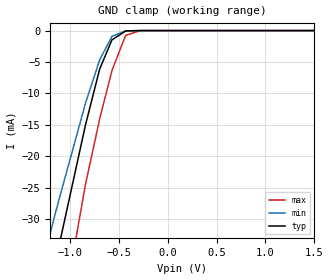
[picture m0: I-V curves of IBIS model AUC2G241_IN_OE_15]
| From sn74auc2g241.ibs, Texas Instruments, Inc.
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[Model]   AUC2G241_IN_OE_15
Model_type  Input
Vinl=0.49
Vinh=1.04
| variable   typ   min   max
C_comp   2.67pF   2.22pF   3.05pF
[Temperature Range]   40   100   -40
| Ambient temperature   25   85   -40
[Voltage range]   1.5   1.4   1.6
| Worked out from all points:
|   GND clamp passes 1 mA (typ) near -0.55 V on its own axis
[GND Clamp]
| AUC2G241_IN_OE_15
|   Voltage   I(typ)   I(min)   I(max)
-3.6V     -223.1mA   -186.8mA   -268.3mA
-1.505V   -63.61mA   -50.93mA   -83.59mA
-1.46V    -60.22mA   -48.13mA   -79.57mA
-1.325V   -50.08mA   -39.79mA   -67.5mA
-1.17V    -38.57mA   -30.39mA   -53.61mA
-1.12V    -34.89mA   -27.41mA   -49.13mA
-840mV    -15.01mA   -11.55mA   -24.46mA
-695mV    -6.121mA   -4.657mA   -14.06mA
-570mV    -1.488mA   -922uA     -6.381mA
-430mV    -73.19uA   -35.15uA   -776.9uA
-280mV    -781.4nA   -560.5nA   -5.358uA
1.5V      174.7pA    268pA      181.1pA
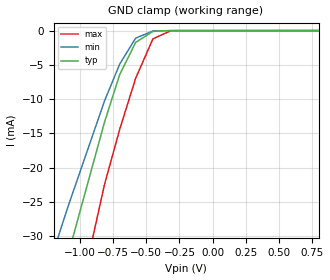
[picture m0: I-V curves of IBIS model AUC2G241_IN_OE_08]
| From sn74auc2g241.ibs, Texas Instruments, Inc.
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[Model]   AUC2G241_IN_OE_08
Model_type  Input
Vinl=0
Vinh=0.8
| variable   typ   min   max
C_comp   2.64pF   2.11pF   3.13pF
[Temperature Range]   40   100   -40
| Ambient temperature   25   85   -40
[Voltage range]   0.8   0.8   0.8
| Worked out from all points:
|   GND clamp passes 1 mA (typ) near -0.55 V on its own axis
[GND Clamp]
| AUC2G241_IN_OE_08
|   Voltage   I(typ)   I(min)   I(max)
-3.6V     -223.1mA   -186.8mA   -268.3mA
-1.465V   -60.59mA   -48.44mA   -80.02mA
-1.33V    -50.46mA   -40.1mA    -67.95mA
-1.285V   -47.1mA    -37.35mA   -63.92mA
-1.125V   -35.26mA   -27.71mA   -49.58mA
-1.09V    -32.7mA    -25.64mA   -46.44mA
-815mV    -13.35mA   -10.25mA   -22.43mA
-700mV    -6.383mA   -4.862mA   -14.38mA
-580mV    -1.725mA   -1.104mA   -6.949mA
-450mV    -123.7uA   -58.98uA   -1.212mA
-315mV    -2.431uA   -1.525uA   -21.15uA
800mV     100.9pA    184.5pA    81.62pA
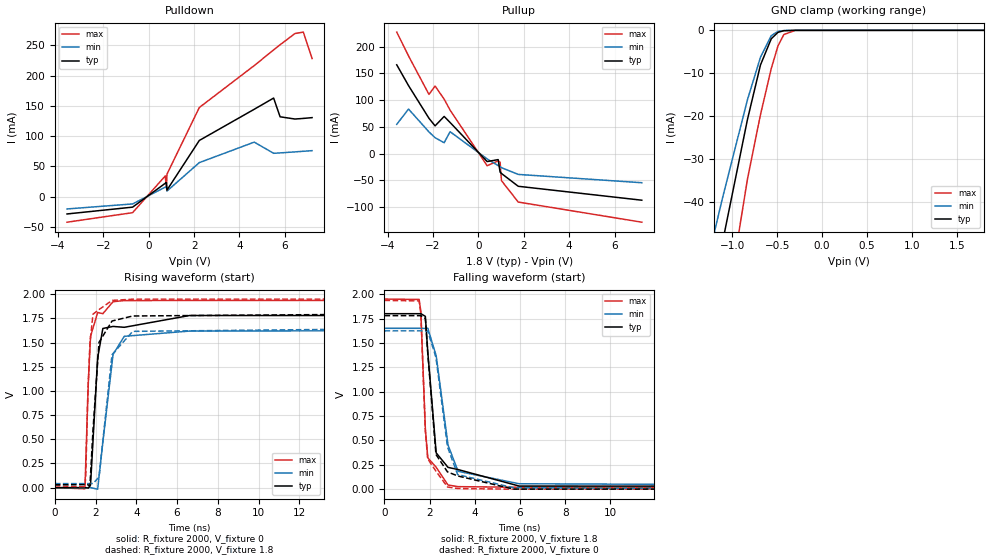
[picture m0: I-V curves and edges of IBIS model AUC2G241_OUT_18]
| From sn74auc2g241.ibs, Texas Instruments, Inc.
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[Model]   AUC2G241_OUT_18
Model_type  3-state
Enable   Active-Low
Vref =   0
Rref =   1000
Cref =   30p
Vmeas =   0.9
| variable   typ   min   max
C_comp   5.16pF   4.61pF   5.42pF
| C_pullup   5.87pF   1.37pF   12.96pF
| C_pulldown   6.42pF   5.22pF   15.40pF
| C_tri-state   5.16pF   4.61pF   5.42pF
[Temperature Range]   40   100   -40
| Ambient temperature   25   85   -40
[Voltage range]   1.8   1.65   1.95
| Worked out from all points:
|   slope of the pulldown table from 0 to 0.27 V, typ, clamps not added: 34.3 ohm
|   slope of the pullup table from 0 to 0.27 V, typ, clamps not added: 24.6 ohm
|   GND clamp passes 1 mA (typ) near -0.53 V on its own axis
|   rising waveform, R_fixture 2000, V_fixture 0: 20-80 % time 308ps typ, 484ps min, 195ps max; typ from 0 V to 1.78 V
|   falling waveform, R_fixture 2000, V_fixture 1.8: 20-80 % time 371ps typ, 597ps min, 225ps max; typ from 1.8 V to 0.031 V
|   rising waveform, R_fixture 2000, V_fixture 1.8: 20-80 % time 307ps typ, 480ps min, 194ps max; typ from 0.031 V to 1.8 V
|   falling waveform, R_fixture 2000, V_fixture 0: 20-80 % time 371ps typ, 594ps min, 225ps max; typ from 1.78 V to 0 V
[GND Clamp]
| AUC2G241_OUT_18
|   Voltage   I(typ)   I(min)   I(max)
-3.6V     -324.8mA   -272.6mA   -395.3mA
-1.48V    -89.78mA   -72.17mA   -119.8mA
-1.435V   -84.84mA   -68.08mA   -113.9mA
-1.3V     -70.1mA    -55.95mA   -96.04mA
-1.105V   -49.1mA    -38.82mA   -70.28mA
-830mV    -20.77mA   -16.17mA   -34.67mA
-685mV    -8.07mA    -6.262mA   -19.65mA
-565mV    -1.967mA   -1.239mA   -8.908mA
-490mV    -465.2uA   -242.6uA   -3.617mA
-425mV    -91.43uA   -52.01uA   -990.1uA
-300mV    -2.28uA    -2.125uA   -16.99uA
1.8V      471.3pA    37.82nA    526.5pA
[Pulldown]
| AUC2G241_OUT_18
|   Voltage   I(typ)   I(min)   I(max)
-3.6V     -28.49mA   -20.22mA   -42.08mA
-710mV    -17.24mA   -11.96mA   -26.36mA
730mV     22.14mA    15.83mA    34.29mA
780mV     23.67mA    17.08mA    13.96mA
805mV     10.91mA    9.302mA    37.17mA
2.23V     92.83mA    56.26mA    147.2mA
4.65V     144.3mA    90.06mA    216.4mA
5.505V    162.8mA    71.64mA    242.3mA
5.79V     131.9mA    72.29mA    250.8mA
6.445V    128.2mA    73.96mA    269.3mA
6.815V    129.2mA    74.96mA    271.7mA
7.2V      130.5mA    76.01mA    228mA
[Pullup]
| AUC2G241_OUT_18
|   Voltage   I(typ)   I(min)   I(max)
-3.6V     166.1mA    54.83mA    227.3mA
-3.08V    127.2mA    83.38mA    182.7mA
-2.18V    66.16mA    40.7mA     110.8mA
-1.91V    51.96mA    29.83mA    126.4mA
-1.51V    69.63mA    20.5mA     101.9mA
-1.25V    58.38mA    41.07mA    81.58mA
385mV     -14.76mA   -9.808mA   -22.53mA
870mV     -11.11mA   -22.27mA   -13.48mA
955mV     -34.36mA   -24.54mA   -15.75mA
1.015V    -36.99mA   -26.15mA   -50.39mA
1.755V    -60.96mA   -38.77mA   -90.45mA
7.2V      -86.99mA   -54.32mA   -128.1mA
[Ramp]
| AUC2G241_OUT_18
| variable   typ   min   max
dV/dt_r   1.08/3.11E-10   0.99/4.92E-10   1.17/1.96E-10
dV/dt_f   1.07/3.71E-10   0.97/6.03E-10   1.16/2.30E-10
R_load = 2000
[Rising Waveform]
| AUC2G241_OUT_18
R_fixture =   2000
C_fixture =   0
L_fixture =   0
V_fixture =   0
V_fixture_min = 0
V_fixture_max = 0
|   Time   V(typ)   V(min)   V(max)
0s        8.423nV    29.16nV    1.166nV
1.48ns    131uV      -8.259uV   -11.51mV
1.645ns   -4.146mV   18.84uV    1.086V
1.755ns   28.65mV    399.6uV    1.565V
2.105ns   1.343V     -15.54mV   1.811V
2.36ns    1.646V     472.7mV    1.799V
2.86ns    1.667V     1.377V     1.923V
3.41ns    1.658V     1.565V     1.934V
6.615ns   1.78V      1.619V     1.936V
20ns      1.78V      1.624V     1.936V
[Falling Waveform]
| AUC2G241_OUT_18
R_fixture =   2000
C_fixture =   0
L_fixture =   0
V_fixture =   1.8
V_fixture_min = 1.65
V_fixture_max = 1.95
|   Time   V(typ)   V(min)   V(max)
0s        1.8V       1.65V      1.95V
1.535ns   1.8V       1.65V      1.946V
1.61ns    1.8V       1.65V      1.822V
1.81ns    1.773V     1.649V     618.1mV
1.92ns    1.403V     1.65V      321.7mV
2.29ns    372.3mV    1.368V     224.4mV
2.815ns   223.5mV    452.6mV    42.64mV
3.26ns    201.2mV    182.8mV    25.82mV
5.97ns    31.64mV    55.6mV     19.59mV
20ns      30.97mV    42.25mV    19.49mV
[Rising Waveform]
| AUC2G241_OUT_18
R_fixture =   2000
C_fixture =   0
L_fixture =   0
V_fixture =   1.8
V_fixture_min = 1.65
V_fixture_max = 1.95
|   Time   V(typ)   V(min)   V(max)
0s        30.94mV    42.24mV    19.47mV
1.48ns    31.07mV    42.23mV    8.597mV
1.52ns    31.21mV    42.23mV    124.3mV
1.62ns    30.43mV    42.23mV    954.2mV
1.725ns   17.52mV    42.44mV    1.489V
1.875ns   592.8mV    42.97mV    1.793V
2.17ns    1.502V     107.6mV    1.841V
2.81ns    1.723V     1.375V     1.936V
3.825ns   1.775V     1.616V     1.949V
20ns      1.8V       1.65V      1.95V
[Falling Waveform]
| AUC2G241_OUT_18
R_fixture =   2000
C_fixture =   0
L_fixture =   0
V_fixture =   0
V_fixture_min = 0
V_fixture_max = 0
|   Time   V(typ)   V(min)   V(max)
0s        1.78V      1.624V     1.936V
1.535ns   1.78V      1.624V     1.931V
1.61ns    1.78V      1.624V     1.806V
1.81ns    1.751V     1.623V     599.3mV
1.915ns   1.398V     1.623V     310.3mV
2.28ns    355.7mV    1.351V     184.8mV
2.79ns    177.2mV    434.7mV    22.28mV
3.24ns    135.9mV    149.5mV    6.16mV
5.715ns   856.7uV    14.42mV    127.5uV
20ns      32.2uV     9.709uV    13.53uV
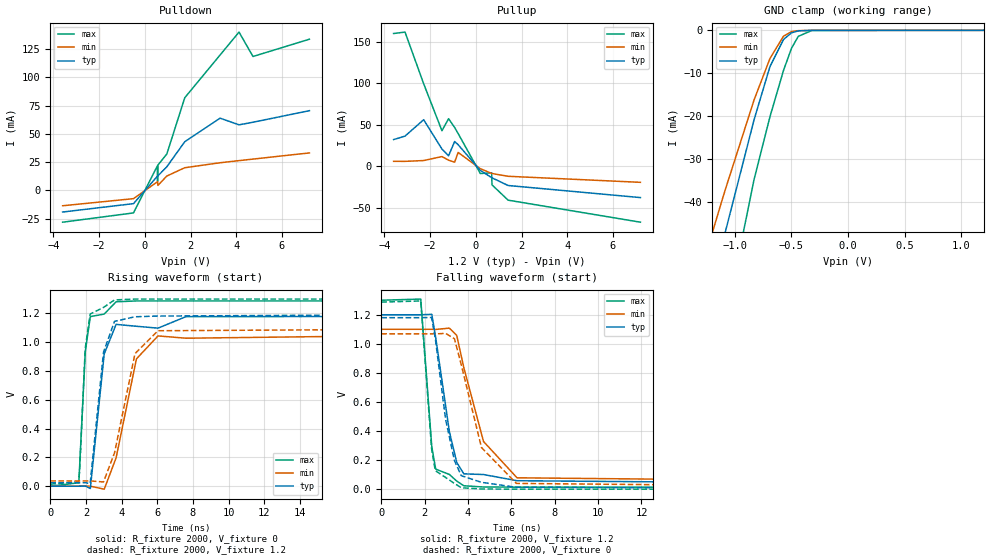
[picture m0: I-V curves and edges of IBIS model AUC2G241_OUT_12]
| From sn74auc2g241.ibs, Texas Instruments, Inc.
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[Model]   AUC2G241_OUT_12
Model_type  3-state
Enable   Active-Low
Vref =   0
Rref =   2000
Cref =   15p
Vmeas =   0.6
| variable   typ   min   max
C_comp   5.39pF   4.85pF   5.66pF
| C_pullup   4.52pF   0.82pF   9.79pF
| C_pulldown   6.19pF   5.48pF   8.81pF
| C_tri-state   5.39pF   4.85pF   5.66pF
[Temperature Range]   40   100   -40
| Ambient temperature   25   85   -40
[Voltage range]   1.2   1.1   1.3
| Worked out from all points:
|   slope of the pulldown table from 0 to 0.18 V, typ, clamps not added: 42.4 ohm
|   slope of the pullup table from 0 to 0.18 V, typ, clamps not added: 38.6 ohm
|   GND clamp passes 1 mA (typ) near -0.53 V on its own axis
|   rising waveform, R_fixture 2000, V_fixture 0: 20-80 % time 581ps typ, 1.04ns min, 318ps max; typ from 0 V to 1.18 V
|   falling waveform, R_fixture 2000, V_fixture 1.2: 20-80 % time 779ps typ, 1.26ns min, 387ps max; typ from 1.2 V to 0.024 V
|   rising waveform, R_fixture 2000, V_fixture 1.2: 20-80 % time 573ps typ, 1.04ns min, 313ps max; typ from 0.024 V to 1.2 V
|   falling waveform, R_fixture 2000, V_fixture 0: 20-80 % time 760ps typ, 1.19ns min, 382ps max; typ from 1.18 V to 0 V
[GND Clamp]
| AUC2G241_OUT_12
|   Voltage   I(typ)   I(min)   I(max)
-3.6V     -324.8mA   -272.6mA   -395.3mA
-1.455V   -87.03mA   -69.89mA   -116.5mA
-1.285V   -68.47mA   -54.61mA   -94.06mA
-1.12V    -50.69mA   -40.11mA   -72.26mA
-1.085V   -46.97mA   -37.09mA   -67.64mA
-830mV    -20.77mA   -16.17mA   -34.67mA
-690mV    -8.435mA   -6.553mA   -20.12mA
-570mV    -2.125mA   -1.36mA    -9.318mA
-500mV    -581.2uA   -306.5uA   -4.204mA
-440mV    -136.4uA   -74.2uA    -1.408mA
-320mV    -4.212uA   -3.691uA   -36.5uA
1.2V      309.4pA    7.674nA    277.4pA
[Pulldown]
| AUC2G241_OUT_12
|   Voltage   I(typ)   I(min)   I(max)
-3.6V     -19.18mA   -13.63mA   -28.17mA
-500mV    -11.75mA   -7.339mA   -19.96mA
545mV     12.46mA    7.541mA    21.58mA
550mV     12.55mA    7.59mA     7.985mA
560mV     12.73mA    7.686mA    8.172mA
570mV     12.91mA    4.373mA    22.34mA
960mV     20.87mA    12.69mA    32.2mA
1.745V    43.07mA    20.04mA    81.99mA
3.29V     63.92mA    24.45mA    119.8mA
4.12V     58mA       26.33mA    140.1mA
4.73V     60.31mA    27.69mA    118.5mA
7.2V      70.54mA    33.15mA    133.8mA
[Pullup]
| AUC2G241_OUT_12
|   Voltage   I(typ)   I(min)   I(max)
-3.6V     32.21mA    6.05mA     159.8mA
-3.1V     36.38mA    6.008mA    161.5mA
-2.285V   56.12mA    6.972mA    99.34mA
-1.485V   20.82mA    11.76mA    42.86mA
-1.195V   12.69mA    7.446mA    57.3mA
-930mV    29.91mA    5.035mA    46.79mA
-775mV    26.01mA    16.75mA    39.41mA
195mV     -4.924mA   -2.842mA   -8.652mA
690mV     -13.63mA   -8.496mA   -7.804mA
705mV     -13.8mA    -8.599mA   -22.25mA
1.41V     -23.04mA   -11.95mA   -40.67mA
7.2V      -37.56mA   -19.23mA   -67.17mA
[Ramp]
| AUC2G241_OUT_12
| variable   typ   min   max
dV/dt_r   0.72/5.86E-10   0.65/1.06E-09   0.77/3.22E-10
dV/dt_f   0.71/7.80E-10   0.64/1.26E-09   0.78/3.90E-10
R_load = 2000
[Rising Waveform]
| AUC2G241_OUT_12
R_fixture =   2000
C_fixture =   0
L_fixture =   0
V_fixture =   0
V_fixture_min = 0
V_fixture_max = 0
|   Time   V(typ)   V(min)   V(max)
0s        7.12nV     30.4nV     740.8pV
1.6ns     -5.976uV   -1.884uV   23.86mV
1.965ns   881uV      -13.18uV   937mV
2.245ns   -15.97mV   -23.53uV   1.178V
3.025ns   919.6mV    -20.62mV   1.196V
3.69ns    1.124V     196.7mV    1.281V
4.83ns    1.111V     884.4mV    1.287V
6.04ns    1.098V     1.044V     1.287V
7.61ns    1.178V     1.028V     1.287V
34.99ns   1.18V      1.069V     1.287V
[Falling Waveform]
| AUC2G241_OUT_12
R_fixture =   2000
C_fixture =   0
L_fixture =   0
V_fixture =   1.2
V_fixture_min = 1.1
V_fixture_max = 1.3
|   Time   V(typ)   V(min)   V(max)
0s        1.2V       1.1V       1.3V
1.82ns    1.2V       1.1V       1.308V
2.33ns    1.203V     1.1V       290.2mV
2.51ns    1.044V     1.099V     138.1mV
3.14ns    396.6mV    1.108V     101.3mV
3.48ns    184.3mV    1.058V     55.8mV
3.805ns   105.5mV    837.1mV    23.43mV
4.715ns   100.7mV    328.1mV    14.99mV
6.26ns    58.09mV    78.23mV    14.02mV
34.99ns   24mV       36.63mV    13.87mV
[Rising Waveform]
| AUC2G241_OUT_12
R_fixture =   2000
C_fixture =   0
L_fixture =   0
V_fixture =   1.2
V_fixture_min = 1.1
V_fixture_max = 1.3
|   Time   V(typ)   V(min)   V(max)
0s        23.98mV    36.63mV    13.86mV
1.58ns    23.97mV    36.63mV    31.96mV
1.645ns   23.97mV    36.62mV    103.3mV
1.96ns    24.76mV    36.62mV    957.1mV
2.235ns   18.07mV    36.61mV    1.196V
2.985ns   931.1mV    29.47mV    1.242V
3.6ns     1.145V     230.8mV    1.294V
4.75ns    1.177V     921.4mV    1.3V
6.04ns    1.182V     1.08V      1.3V
34.99ns   1.2V       1.1V       1.3V
[Falling Waveform]
| AUC2G241_OUT_12
R_fixture =   2000
C_fixture =   0
L_fixture =   0
V_fixture =   0
V_fixture_min = 0
V_fixture_max = 0
|   Time   V(typ)   V(min)   V(max)
0s        1.18V      1.069V     1.287V
1.82ns    1.18V      1.069V     1.295V
2.32ns    1.181V     1.069V     279.1mV
2.49ns    1.039V     1.068V     127.8mV
2.965ns   480.6mV    1.072V     80.75mV
3.375ns   196.7mV    1.035V     39.21mV
3.69ns    92.68mV    855.5mV    9.869mV
4.62ns    47.08mV    286.9mV    1.081mV
6.23ns    12.86mV    39.58mV    149.4uV
34.99ns   21.62uV    -67.63nV   8.286uV
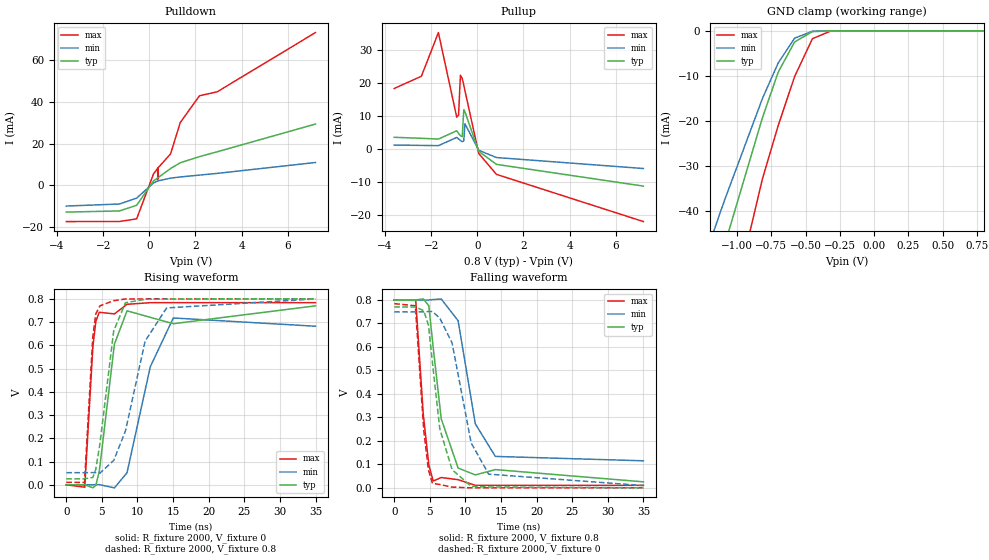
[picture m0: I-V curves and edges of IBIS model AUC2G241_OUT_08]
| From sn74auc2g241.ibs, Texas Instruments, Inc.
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[Model]   AUC2G241_OUT_08
Model_type  3-state
Enable   Active-Low
Vref =   0
Rref =   2000
Cref =   15p
Vmeas =   0.4
| variable   typ   min   max
C_comp   5.50pF   5.00pF   5.68pF
| C_pullup   5.67pF   1.14pF   7.93pF
| C_pulldown   6.37pF   5.71pF   6.83pF
| C_tri-state   5.50pF   5.00pF   5.68pF
[Temperature Range]   40   100   -40
| Ambient temperature   25   85   -40
[Voltage range]   0.8   0.8   0.8
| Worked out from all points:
|   slope of the pulldown table from 0 to 0.12 V, typ, clamps not added: 77.5 ohm
|   slope of the pullup table from 0 to 0.12 V, typ, clamps not added: 94 ohm
|   GND clamp passes 1 mA (typ) near -0.53 V on its own axis
|   rising waveform, R_fixture 2000, V_fixture 0: 20-80 % time 1.82ns typ, 2.91ns min, 910ps max; typ from 0 V to 0.77 V
|   falling waveform, R_fixture 2000, V_fixture 0.8: 20-80 % time 2.4ns typ, 2.33ns min, 1.26ns max; typ from 0.8 V to 0.026 V
|   rising waveform, R_fixture 2000, V_fixture 0.8: 20-80 % time 1.83ns typ, 3.5ns min, 869ps max; typ from 0.025 V to 0.8 V
|   falling waveform, R_fixture 2000, V_fixture 0: 20-80 % time 2.04ns typ, 2.87ns min, 1.16ns max; typ from 0.77 V to 0 V
[GND Clamp]
| AUC2G241_OUT_08
|   Voltage   I(typ)   I(min)   I(max)
-3.6V     -324.8mA   -272.6mA   -395.3mA
-1.465V   -88.13mA   -70.8mA    -117.8mA
-1.33V    -73.37mA   -58.63mA   -100mA
-1.285V   -68.47mA   -54.61mA   -94.06mA
-1.125V   -51.23mA   -40.54mA   -72.92mA
-1.09V    -47.5mA    -37.52mA   -68.3mA
-815mV    -19.32mA   -15.04mA   -32.89mA
-700mV    -9.187mA   -7.147mA   -21.07mA
-580mV    -2.465mA   -1.627mA   -10.15mA
-450mV    -176.7uA   -94.05uA   -1.748mA
-315mV    -3.612uA   -3.219uA   -30.25uA
800mV     222.9pA    406.9pA    175.5pA
[Pulldown]
| AUC2G241_OUT_08
|   Voltage   I(typ)   I(min)   I(max)
-3.6V     -12.84mA   -9.953mA   -17.38mA
-1.295V   -12.29mA   -8.968mA   -17.35mA
-550mV    -9.589mA   -6.157mA   -16.09mA
180mV     2.098mA    1.151mA    5.42mA
360mV     3.518mA    2.063mA    8.134mA
365mV     3.559mA    2.087mA    2.788mA
370mV     3.599mA    2.112mA    8.262mA
920mV     8.04mA     3.431mA    15.04mA
1.34V     10.79mA    3.992mA    30.07mA
2.175V    13.75mA    4.895mA    42.92mA
2.94V     16.06mA    5.706mA    44.8mA
7.2V      29.35mA    10.93mA    73.19mA
[Pullup]
| AUC2G241_OUT_08
|   Voltage   I(typ)   I(min)   I(max)
-3.6V     3.467mA    1.12mA     18.22mA
-2.42V    3.164mA    1.017mA    21.93mA
-1.685V   2.933mA    943.1uA    35.13mA
-890mV    5.445mA    3.423mA    9.571mA
-810mV    4.651mA    2.966mA    10.18mA
-730mV    3.946mA    2.515mA    22.25mA
-650mV    3.665mA    2.133mA    21.22mA
-585mV    11.79mA    2.387mA    19.26mA
-535mV    11.19mA    7.562mA    17.59mA
65mV      -779.4uA   -459.6uA   -1.427mA
830mV     -4.718mA   -2.65mA    -7.736mA
7.2V      -11.29mA   -5.969mA   -22.01mA
[Ramp]
| AUC2G241_OUT_08
| variable   typ   min   max
dV/dt_r   0.47/1.84E-09   0.46/3.46E-09   0.48/9.23E-10
dV/dt_f   0.47/2.40E-09   0.43/2.62E-09   0.48/1.26E-09
R_load = 2000
[Rising Waveform]
| AUC2G241_OUT_08
R_fixture =   2000
C_fixture =   0
L_fixture =   0
V_fixture =   0
V_fixture_min = 0
V_fixture_max = 0
|   Time   V(typ)   V(min)   V(max)
0s        8.744nV    49.66nV    546.6pV
2.59ns    9.887uV    -34.81uV   -10.6mV
3.735ns   -12.83mV   171.3uV    593.6mV
4.15ns    -2.351mV   531.2uV    703.4mV
4.635ns   57.55mV    627.1uV    742.2mV
6.76ns    605.5mV    -13.26mV   735.4mV
8.53ns    748.5mV    51.79mV    776.6mV
11.8ns    720.5mV    508.2mV    783.6mV
15.03ns   693.1mV    717.8mV    783.7mV
34.99ns   770mV      682.2mV    783.7mV
[Falling Waveform]
| AUC2G241_OUT_08
R_fixture =   2000
C_fixture =   0
L_fixture =   0
V_fixture =   0.8
V_fixture_min = 0.8
V_fixture_max = 0.8
|   Time   V(typ)   V(min)   V(max)
0s        800mV      800mV      800mV
3.025ns   799.2mV    800mV      797.6mV
4.075ns   804.2mV    799.4mV    315.9mV
4.86ns    775mV      799.3mV    98.53mV
5.47ns    599mV      801.3mV    28.88mV
6.605ns   293.8mV    803.6mV    43.97mV
8.975ns   84.22mV    711.3mV    34.76mV
11.39ns   55.13mV    272.4mV    10.91mV
14.2ns    77.65mV    133.8mV    10.66mV
34.99ns   25.56mV    115.1mV    10.61mV
[Rising Waveform]
| AUC2G241_OUT_08
R_fixture =   2000
C_fixture =   0
L_fixture =   0
V_fixture =   0.8
V_fixture_min = 0.8
V_fixture_max = 0.8
|   Time   V(typ)   V(min)   V(max)
0s        25.46mV    52.12mV    10.6mV
2.56ns    25.49mV    52.13mV    9.872mV
3.73ns    31.55mV    52.35mV    638.7mV
4.14ns    66.46mV    51.96mV    734.8mV
4.715ns   175.3mV    50.03mV    769.8mV
6.66ns    662.4mV    104.7mV    792.2mV
8.31ns    783.3mV    231.6mV    799.6mV
11.07ns   798.1mV    618.3mV    799.8mV
14.09ns   799.2mV    761mV      799.9mV
34.99ns   800mV      799.6mV    800mV
[Falling Waveform]
| AUC2G241_OUT_08
R_fixture =   2000
C_fixture =   0
L_fixture =   0
V_fixture =   0
V_fixture_min = 0
V_fixture_max = 0
|   Time   V(typ)   V(min)   V(max)
0s        770mV      748.6mV    783.8mV
2.97ns    769.6mV    748.5mV    774.9mV
4.145ns   754.2mV    748.8mV    245.3mV
4.81ns    692.4mV    750.3mV    75.77mV
5.375ns   531.8mV    750.1mV    19.4mV
6.4ns     251mV      722.3mV    14.24mV
8.13ns    77.41mV    616.6mV    3.099mV
10.81ns   6.318mV    190.9mV    116uV
13.27ns   3.745mV    58.27mV    56.42uV
34.99ns   57.81uV    9.678mV    12.43uV
